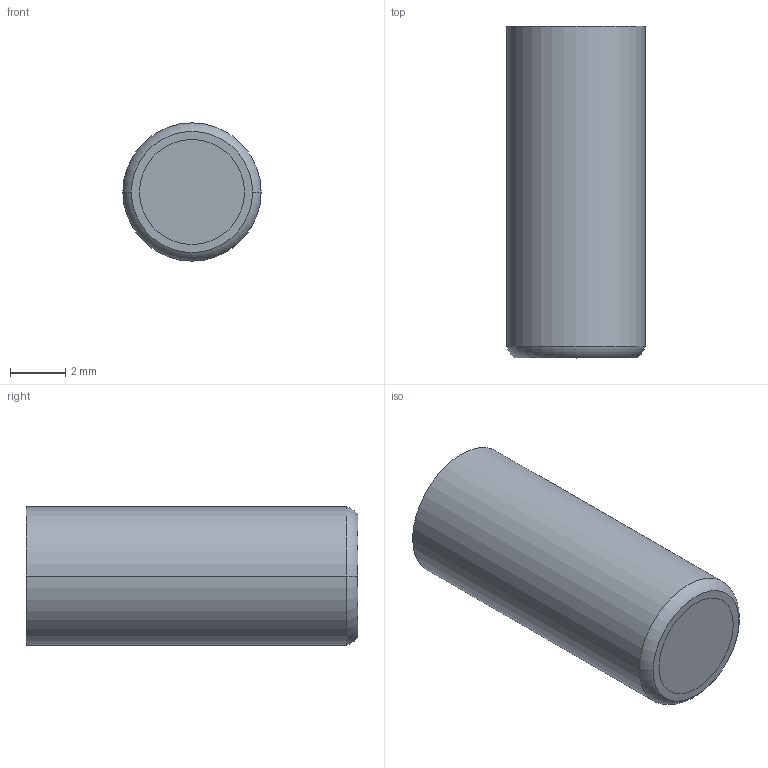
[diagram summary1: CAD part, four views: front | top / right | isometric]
STEP (ISO 10303-21) file: header records copied from the file, then geometry measured from it (millimetres).
FILE_DESCRIPTION (( 'STEP AP214' ), '1' );
FILE_NAME ('FA 053012-20.STEP', '2013-10-01T08:26:33', ( '' ), ( '' ), 'SwSTEP 2.0', 'SolidWorks 2011', '' );
FILE_SCHEMA (( 'AUTOMOTIVE_DESIGN' ));
Length unit declared in the file: millimetre
Products named in the file (6): FA 053012-20; 9FA 053012; IA 307520; FA 053000-2; FA 053000-3; FA 053000-1
Assembly tree (5 placements, depth 2):
  FA 053012-20
    FA 053000-1
    FA 053000-3
    IA 307520
    FA 053000-2
    9FA 053012
Bounding box: 5 x 12 x 5 mm (x, y, z)
Volume: 204.4 mm3; surface area: 601.2 mm2
Topology: 5 solids, 5 shells, 302 faces, 755 edges, 498 vertices
Faces by surface type: cylinder 147, plane 137, cone 12, bspline 4, torus 2
Entity records: 11419 total; most frequent: CARTESIAN_POINT 3579, DIRECTION 1671, ORIENTED_EDGE 1510, EDGE_CURVE 755, AXIS2_PLACEMENT_3D 620, VERTEX_POINT 498, LINE 431, VECTOR 431
One B-rep face of a CAD part: STEP entity #5523.
In plain terms, the planar face has unit normal (0, 1, 0).
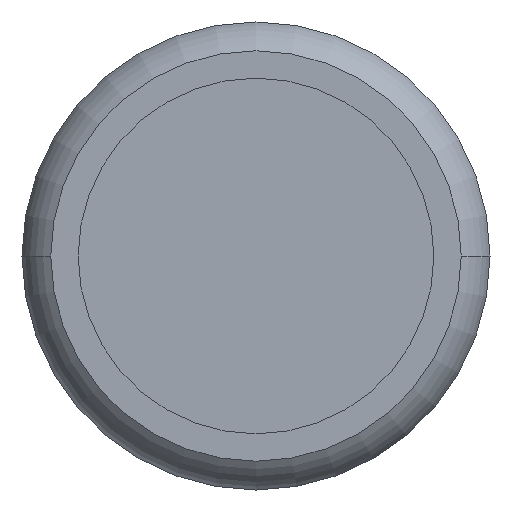
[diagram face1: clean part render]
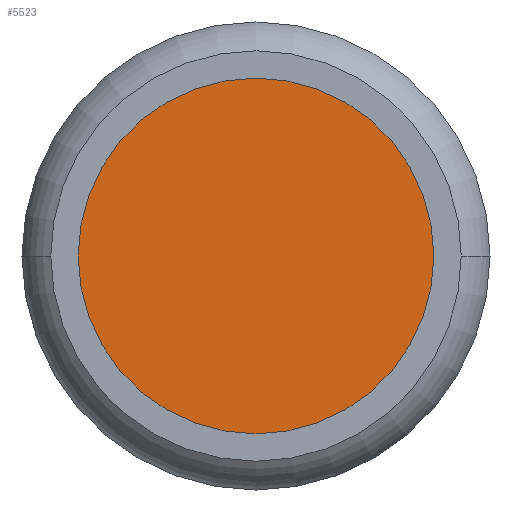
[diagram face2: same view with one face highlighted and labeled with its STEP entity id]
Its self-contained STEP definition (entity closure, numbers rounded to 3 decimals):
#375 = EDGE_LOOP ( 'NONE', ( #1067, #1032 ) ) ;
#831 = VERTEX_POINT ( 'NONE', #8272 ) ;
#843 = VERTEX_POINT ( 'NONE', #8234 ) ;
#1032 = ORIENTED_EDGE ( 'NONE', *, *, #9828, .F. ) ;
#1067 = ORIENTED_EDGE ( 'NONE', *, *, #9800, .F. ) ;
#2159 = PLANE ( 'NONE',  #10976 ) ;
#2170 = CARTESIAN_POINT ( 'NONE',  ( -2.192, 2.45, 10. ) ) ;
#2174 = FACE_OUTER_BOUND ( 'NONE', #375, .T. ) ;
#2182 = DIRECTION ( 'NONE',  ( 0., -1., 0. ) ) ;
#2183 = DIRECTION ( 'NONE',  ( 0., 0., -1. ) ) ;
#2770 = CIRCLE ( 'NONE', #2799, 1.9 ) ;
#2780 = CIRCLE ( 'NONE', #2802, 1.9 ) ;
#2799 = AXIS2_PLACEMENT_3D ( 'NONE', #3437, #3450, #3427 ) ;
#2802 = AXIS2_PLACEMENT_3D ( 'NONE', #3530, #3536, #3544 ) ;
#3427 = DIRECTION ( 'NONE',  ( 0., 0., -1. ) ) ;
#3437 = CARTESIAN_POINT ( 'NONE',  ( 0., 2.45, 0. ) ) ;
#3450 = DIRECTION ( 'NONE',  ( 0., -1., 0. ) ) ;
#3530 = CARTESIAN_POINT ( 'NONE',  ( 0., 2.45, 0. ) ) ;
#3536 = DIRECTION ( 'NONE',  ( 0., -1., 0. ) ) ;
#3544 = DIRECTION ( 'NONE',  ( 0., 0., -1. ) ) ;
#5523 = ADVANCED_FACE ( 'NONE', ( #2174 ), #2159, .F. ) ;
#8234 = CARTESIAN_POINT ( 'NONE',  ( 0., 2.45, 1.9 ) ) ;
#8272 = CARTESIAN_POINT ( 'NONE',  ( 0., 2.45, -1.9 ) ) ;
#9800 = EDGE_CURVE ( 'NONE', #843, #831, #2770, .T. ) ;
#9828 = EDGE_CURVE ( 'NONE', #831, #843, #2780, .T. ) ;
#10976 = AXIS2_PLACEMENT_3D ( 'NONE', #2170, #2182, #2183 ) ;
